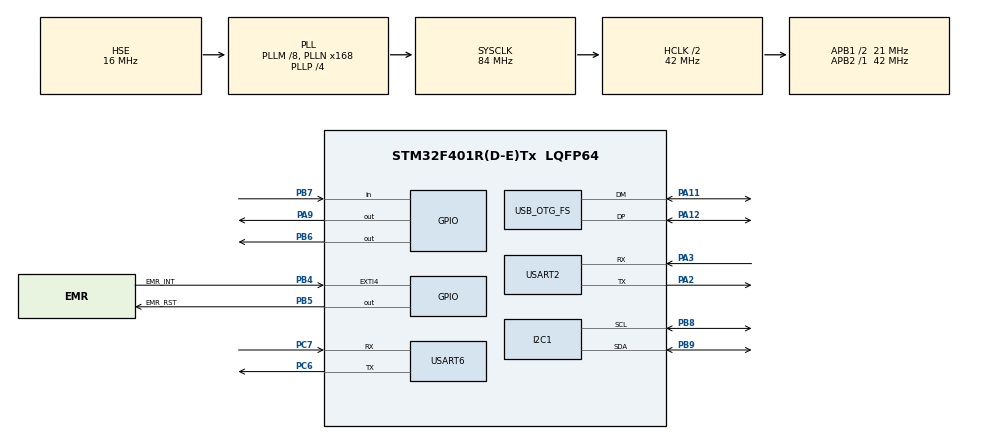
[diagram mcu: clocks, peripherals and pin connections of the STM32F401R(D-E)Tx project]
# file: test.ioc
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I2C1.I2C_Mode=I2C_Fast
Mcu.Family=STM32F4
Mcu.Name=STM32F401R(D-E)Tx
Mcu.Package=LQFP64
NVIC.EXTI4_IRQn=true\:0\:0\:false\:false\:true\:true\:true
NVIC.I2C1_ER_IRQn=true\:0\:0\:false\:false\:true\:true\:true
NVIC.I2C1_EV_IRQn=true\:0\:0\:false\:false\:true\:true\:true
NVIC.OTG_FS_IRQn=true\:0\:0\:false\:false\:true\:false\:true
NVIC.PriorityGroup=NVIC_PRIORITYGROUP_4
NVIC.USART2_IRQn=true\:1\:0\:true\:false\:true\:true\:true
NVIC.USART6_IRQn=true\:3\:0\:true\:false\:true\:true\:true
PA11.Mode=Device_Only
PA11.Signal=USB_OTG_FS_DM
PA12.Mode=Device_Only
PA12.Signal=USB_OTG_FS_DP
PA2.Mode=Asynchronous
PA2.Signal=USART2_TX
PA3.Mode=Asynchronous
PA3.Signal=USART2_RX
PA9.Signal=GPIO_Output
PB4.GPIO_Label=EMR_INT
PB4.GPIO_ModeDefaultEXTI=GPIO_MODE_IT_RISING_FALLING
PB4.Signal=GPXTI4
PB5.GPIO_Label=EMR_RST
PB5.PinState=GPIO_PIN_SET
PB5.Signal=GPIO_Output
PB6.Signal=GPIO_Output
PB7.Signal=GPIO_Input
PB8.Mode=I2C
PB8.Signal=I2C1_SCL
PB9.Mode=I2C
PB9.Signal=I2C1_SDA
PC14-OSC32_IN.Mode=LSE-External-Oscillator
PC14-OSC32_IN.Signal=RCC_OSC32_IN
PC15-OSC32_OUT.Mode=LSE-External-Oscillator
PC15-OSC32_OUT.Signal=RCC_OSC32_OUT
PC6.Mode=Asynchronous
PC6.Signal=USART6_TX
PC7.Mode=Asynchronous
PC7.Signal=USART6_RX
PH0\ -\ OSC_IN.Mode=HSE-External-Oscillator
PH0\ -\ OSC_IN.Signal=RCC_OSC_IN
PH1\ -\ OSC_OUT.Mode=HSE-External-Oscillator
PH1\ -\ OSC_OUT.Signal=RCC_OSC_OUT
ProjectManager.HeapSize=0x400
ProjectManager.StackSize=0x800
ProjectManager.TargetToolchain=MDK-ARM V5.27
RCC.48MHZClocksFreq_Value=48000000
RCC.AHBCLKDivider=RCC_SYSCLK_DIV2
RCC.AHBFreq_Value=42000000
RCC.APB1CLKDivider=RCC_HCLK_DIV2
RCC.APB1Freq_Value=21000000
RCC.APB1TimFreq_Value=42000000
RCC.APB2Freq_Value=42000000
RCC.APB2TimFreq_Value=42000000
RCC.CortexFreq_Value=42000000
RCC.HCLKFreq_Value=42000000
RCC.HSE_VALUE=16000000
RCC.HSI_VALUE=16000000
RCC.PLLM=8
RCC.PLLN=168
RCC.PLLP=RCC_PLLP_DIV4
RCC.PLLQ=7
RCC.SYSCLKFreq_VALUE=84000000
RCC.SYSCLKSource=RCC_SYSCLKSOURCE_PLLCLK
RCC.VCOOutputFreq_Value=336000000
USART2.VirtualMode=VM_ASYNC
USART6.VirtualMode=VM_ASYNC
USB_DEVICE.CLASS_NAME_FS=CUSTOM_HID
USB_DEVICE.VirtualMode-CUSTOM_HID_FS=CustomHid
USB_DEVICE.VirtualModeFS=Custom_Hid_FS
USB_OTG_FS.VirtualMode=Device_Only
VP_USB_DEVICE_VS_USB_DEVICE_CUSTOM_HID_FS.Mode=CUSTOM_HID_FS
board=custom

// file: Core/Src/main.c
/* USER CODE BEGIN Header */
/**
  ******************************************************************************
  * @file           : main.c
  * @brief          : Main program body
  ******************************************************************************
  * @attention
  *
  * <h2><center>&copy; Copyright (c) 2021 STMicroelectronics.
  * All rights reserved.</center></h2>
  *
  * This software component is licensed by ST under Ultimate Liberty license
  * SLA0044, the "License"; You may not use this file except in compliance with
  * the License. You may obtain a copy of the License at:
  *                             www.st.com/SLA0044
  *
  ******************************************************************************
  */
/* USER CODE END Header */
#include "main.h"
#include "usb_device.h"

/* USER CODE BEGIN Includes */
#include "usbd_custom_hid_if.h"
#include <stdio.h>
#include "sw_iic.h"
/* USER CODE END Includes */

/* USER CODE BEGIN PTD */
uint8_t EMR_I2C_ADDR_8BIT = 0x13 ;
#define EMR_I2C_PACKET_SIZE 17
#define REPORT_ID 0x02
uint8_t ROTATION_0_CMD[17] = { 0x11,0xff,0xff,0xff,0xff,0xff,0xff,0xff,0xff,0xff,0xff,0xff,0xff,0xff,0xff,0xff,0x00 };
uint8_t ROTATION_90_CMD[17] = { 0x11,0xff,0xff,0xff,0xff,0xff,0xff,0xff,0xff,0xff,0xff,0xff,0xff,0xff,0xff,0xff,0x01 };
uint8_t EMR_INT = 0 ;
uint8_t OSD_ON = 0 ;
uint8_t OSD_EVENT_RELEASE = 0 ;
extern I2C_HandleTypeDef hi2c1;
extern UART_HandleTypeDef huart6;
extern GPIO_InitTypeDef GPIO_InitStruct ;
uint8_t pData[EMR_I2C_PACKET_SIZE];
uint8_t send_data[128];
uint8_t  aRxBuffer[64];

uint8_t i ;
volatile uint8_t  page_buf[512];

uint8_t  page_buf_full_idx = 0 ,flag_start_fill_page_buf = 0;

uint8_t test_buf[64];

uint32_t press_cnt = 0 ;

/*
	0: pen mode
	1: zoom mode
*/
uint8_t working_mode = 0;

typedef struct
{
	uint8_t KEYPAD_ID ; // 0x01
	/* b0 : left ctrl
		b1 : left shift
		b2 : left alt
		b3 : left GUI
		b4 : right ctrl
		b5 : right shift
		b6 : right alt
		b7 : right GUI
	*/
	uint8_t MODIFIER ;

	uint8_t RESERVED ;
	uint8_t KEYCODE1 ; //0x56 Keypad - ; 0x57 keypad +
	uint8_t KEYCODE2 ;
	uint8_t KEYCODE3 ;
	uint8_t KEYCODE4 ;
	uint8_t KEYCODE5 ;
	uint8_t KEYCODE6 ;
}KeyboardHID ;

KeyboardHID keyboard_hid = {1,0,0,0,0,0,0,0,0};

#define MAX_X   29376
#define MAX_Y	 16524
/* USER CODE END PTD */

/* USER CODE BEGIN PD */
void Handle_EMR_Data();

/* USER CODE END PD */

I2C_HandleTypeDef hi2c1;

UART_HandleTypeDef huart2;
UART_HandleTypeDef huart6;

/* USER CODE BEGIN PV */
extern USBD_HandleTypeDef hUsbDeviceFS;

/* USER CODE END PV */

void SystemClock_Config(void);
static void MX_GPIO_Init(void);
static void MX_I2C1_Init(void);
static void MX_USART2_UART_Init(void);
static void MX_USART6_UART_Init(void);

/* USER CODE BEGIN 0 */
void Delay()
{
	uint16_t d = 0xf;
	while(d--) ;
}
int fputc(int32_t ch, FILE *f)
{
  //  while((USART6->SR&0X40)==0);
   // USART6->DR = (uint8_t) ch;
	HAL_UART_Transmit(&huart6,(uint8_t *)&ch,1,1000);

    return ch;
}

/* Send OSD control data to scaler */
uint8_t Send_OSD_Control_to_Scaler(uint8_t event,uint8_t x_lo,uint8_t x_hi,uint8_t y_lo , uint8_t y_hi)
{
	uint8_t Ack,CheckSum;
	uint8_t data[4] ;
	data[0] = x_lo ;
	data[1] = x_hi ;
	data[2] = y_lo ;
	data[3] = y_hi ;
	//IIC_Start();
	//T_IIC_Tx(0x6e);
	//T_IIC_Tx(event);
	//T_IIC_Tx(x_lo);
	//T_IIC_Tx(x_hi);
	//T_IIC_Tx(y_lo);
	//T_IIC_Tx(y_hi);
	//IIC_Stop();
	HAL_UART_Transmit(&huart2,data,4,1000);
	return Ack;
}

void keypad_zoom_in()
{
	keyboard_hid.KEYPAD_ID = 0x01 ;
	keyboard_hid.MODIFIER = 1 ; //b0=left ctrl
	keyboard_hid.KEYCODE1 = 0x57 ; // keypad +

	USBD_CUSTOM_HID_SendReport_FS((uint8_t*)&keyboard_hid , sizeof(keyboard_hid));
	HAL_Delay(5);
	keyboard_hid.MODIFIER = 0 ; // release
	keyboard_hid.KEYCODE1 = 0 ; // release
	USBD_CUSTOM_HID_SendReport_FS((uint8_t*)&keyboard_hid , sizeof(keyboard_hid));
	HAL_Delay(10);

}

void keypad_zoom_out()
{
	keyboard_hid.KEYPAD_ID = 0x01 ;
	keyboard_hid.MODIFIER = 1 ; //b0=left ctrl
	keyboard_hid.KEYCODE1 = 0x56 ; // keypad -

	USBD_CUSTOM_HID_SendReport_FS((uint8_t*)&keyboard_hid , sizeof(keyboard_hid));
	HAL_Delay(5);
	keyboard_hid.MODIFIER = 0 ; // release
	keyboard_hid.KEYCODE1 = 0 ; // release
	USBD_CUSTOM_HID_SendReport_FS((uint8_t*)&keyboard_hid , sizeof(keyboard_hid));
	HAL_Delay(10);

}

void handle_buffer() {

#if 0
   uint16_t i ;
	printf("usb reveive : \n\r");
  for(i=0 ; i<64 ;i++)
  {
	  printf(",0x%x",aRxBuffer[i]);
  }
	printf("\n\r");
#endif

//	USBD_CUSTOM_HID_SendReport_FS(aRxBuffer,8) ;

	if(flag_start_fill_page_buf)
	{
		if((memcmp(aRxBuffer,CMD_SET_BANK0,11)!= 0)
			&& ( memcmp(aRxBuffer,CMD_SET_BANK1,11)!= 0)
			&& ( memcmp(aRxBuffer,CMD_SET_BANK2,11)!= 0)
			&& ( memcmp(aRxBuffer,CMD_SET_BANK3,11)!= 0)
			&& ( memcmp(aRxBuffer,CMD_START_FLASH,11)!= 0)
			&& ( memcmp(aRxBuffer,CMD_END_FLASH,11)!= 0))
		{

			if(page_buf_full_idx < 16)
			{
				memcpy((page_buf+(32*page_buf_full_idx)),aRxBuffer,32);
				page_buf_full_idx++ ;

			}
		}
		 //USBD_CUSTOM_HID_SendReport_FS(rxBuffer,8) ;
    }
}

void ResetEMR()
{
	HAL_GPIO_WritePin(EMR_RST_GPIO_Port,GPIO_PIN_5,GPIO_PIN_SET);
	HAL_GPIO_WritePin(EMR_RST_GPIO_Port,GPIO_PIN_5,GPIO_PIN_RESET);
	Delay();
	HAL_GPIO_WritePin(EMR_RST_GPIO_Port,GPIO_PIN_5,GPIO_PIN_SET);
//	printf("force to EMR RESET !\n\r");
}

uint8_t EMR_Alive_Check(void)
{
    HAL_StatusTypeDef i2c_res;
    uint8_t	addr_w=0x12;
    //uint8_t	addr_r=0x13;

    i2c_res = HAL_I2C_Master_Transmit( &hi2c1, addr_w, 0x00, 0x01, 10000 );
    if (i2c_res != HAL_OK)
    {

        printf( "EMR Alive Check ERROR. Res = 0x%02X  \r\n",i2c_res );

        ResetEMR();
    }
    else
    {

     //   printf( "EMR Alive Check PASS !!  \r\n");

    }
    return i2c_res;

}

int16_t x ,y ,p;

void Handle_EMR_to_USB()
{

		send_data[0]=REPORT_ID;

		send_data[1]=(pData[3]);

		/*x*/
		x = MAX_X-(pData[4] + (pData[5]<<8)) ;
		if(x<0)return;
		//send_data[2]=(pData[4]);
		//send_data[3]=(pData[5]);
		send_data[2]=(x&0xff);
		send_data[3]=(x>>8);

		/*y*/
		y = MAX_Y-(pData[6] + (pData[7]<<8) ) ;
	   if(y<0)return;
		//send_data[4]=(pData[6]);
		//send_data[5]=(pData[7]);
		send_data[4] = y&0xff ;
		send_data[5]= (y >>8) ;

		/*pressure*/
		send_data[6]=pData[8];//low byte
		send_data[7]=pData[9];//high byte

		 USBD_CUSTOM_HID_SendReport_FS(send_data,8) ;
	//	 send_data[0]=0x03 ;
	//	 USBD_CUSTOM_HID_SendReport_FS(send_data,9) ;

}

uint16_t temp_y ;
uint16_t falling_cnt = 0 ;
uint16_t rising_cnt = 0 ;

#define ZOOM_ONE_SHOT

void Handle_ZOOM_IN_OUT ()
{

	//printf("Tip Switch = %x\n\r",(pData[3]&0x01));
	//uint8_t Tip_Switch = pData[3]&0x01 ;
	y = MAX_Y-(pData[6] + (pData[7]<<8) ) ;
	//printf("Tip Switch = %x\n\r",Tip_Switch);
	//if(Tip_Switch == 1)
	{
		if(y>(temp_y+30))
		{
			falling_cnt ++ ;
			if(falling_cnt == 5)
			{

				keypad_zoom_in();
				falling_cnt =0 ;
				rising_cnt = 0 ;
				temp_y = 0 ;
			}
		}

		else if(y<temp_y-30)
		{
			rising_cnt ++ ;
			if(rising_cnt == 6)
			{

				keypad_zoom_out();
				falling_cnt =0 ;
				rising_cnt = 0 ;
				temp_y = 0 ;
			}
		}
		temp_y = y ;
	}

}

void Handle_EMR_Data ()
{
	uint8_t Barrel_Switch = 0 ;
	uint8_t Tip_Switch = 0 ;
	uint16_t pressure = 0 ;

	if(EMR_INT)
	{
	//	printf("EMR INT\n\r");
		HAL_StatusTypeDef status;

		/*一直讀到中斷Rising Trigger */
		while(1)
		{
			if(EMR_INT == 0) break;
			status =  HAL_I2C_Master_Receive(&hi2c1, EMR_I2C_ADDR_8BIT, pData, EMR_I2C_PACKET_SIZE, 100);

			if(status == HAL_ERROR)
			{
				printf("i2c HAL_ERROR\n\r");
				ResetEMR() ;
				break;

			}
			else if(status == HAL_BUSY)
			{
				printf("i2c HAL_BUSY\n\r");
				ResetEMR() ;
				break;
			}
			else if(status == HAL_TIMEOUT)
			{
				printf("i2c HAL_TIMEOUT\n\r");
				ResetEMR() ;
				break;
			}
			else if (status == HAL_OK)
			{
#if 0
			printf("receive EMR Data %d\n\r",EMR_I2C_PACKET_SIZE);
			for(i=0;i<EMR_I2C_PACKET_SIZE ; i++ )
				printf("%x, ",pData[i]);
			printf("\n\r");
//			printf("Tx=%d , Ty=%d \n\r",(pData[11]+pData[12]<<8),(pData[13]+pData[14]<<8));
#endif
	//	 USBD_CUSTOM_HID_SendReport_FS(pData,EMR_I2C_PACKET_SIZE) ;

			//send_data[6]=pData[8];//low byte
		   //send_data[7]=pData[9];//high byte

#if 0
				printf("Tip Switch = %x\n\r",(pData[3]&0x01));
				printf("Barrel Switch = %x\n\r",(pData[3]&0x02)>>1);
				printf("Eraser = %x\n\r",(pData[3]&0x04)>>2);
				printf("Invert = %x\n\r",(pData[3]&0x08)>>3);
				printf("In Range = %x\n\r",(pData[3]&0x20)>>5);
				printf("Pressure = %x\n\r",(pData[8] + (pData[9] <<8)));
				printf("*************************************\n\r");
#endif
			/*test function" OSD_ON always 1*/
			OSD_ON = 1 ;
			/*check OSD detect pin , normal mode*/
			if(OSD_ON == 0)
			{

				Barrel_Switch = (pData[3]&0x02)>>1 ;
				Tip_Switch = pData[3]&0x01 ;
				if(Barrel_Switch == 1 && Tip_Switch == 1)
				{
					press_cnt ++ ;
					if(press_cnt % 29 ==0)
					{

						Handle_ZOOM_IN_OUT ();
					}
				}

				else if(Barrel_Switch == 1 && Tip_Switch == 0)
				{
					falling_cnt =0 ;
					rising_cnt = 0 ;
					temp_y = 0 ;

					press_cnt = 0 ;
				}
				else
				{
					falling_cnt =0 ;
					rising_cnt = 0 ;
					temp_y = 0 ;

					press_cnt = 0 ;
					Handle_EMR_to_USB();
				}

			}
			else if(OSD_ON == 1)
			{
				/*check OSD detect pin , OSD mode*/
				pressure = pData[8] + (pData[9] <<8) ;
				if(pressure == 0)
				{
					OSD_EVENT_RELEASE = 1;

				}

				if(OSD_EVENT_RELEASE == 1)
				{
					if(pressure > 1000 )
					{
						OSD_EVENT_RELEASE = 0;
						/* Send data to scaler to control menu  */
						Send_OSD_Control_to_Scaler(0x61,0x62,0x63,0x64,0x65);
					//	printf("click!");

					}
				}

			}

		}
	}
		EMR_Alive_Check();

}

}

/* EMR Interrupt */
void HAL_GPIO_EXTI_Callback(uint16_t GPIO_Pin)
{
	if(GPIO_Pin == EMR_INT_Pin)
	{
		if(HAL_GPIO_ReadPin(EMR_INT_GPIO_Port,EMR_INT_Pin) == RESET)
		{
			EMR_INT = 1;
		//	printf("1");
		}
		else
		{
			EMR_INT = 0;
		//	printf("0");
		}

	//	Handle_EMR_Data ();
	}
	if(GPIO_Pin == GPIO_PIN_2)
	{
	//	printf("2\n\r");
	}
#if 0
	if(GPIO_Pin == OSD_MENU_DETECT_Pin)
	{
		if(HAL_GPIO_ReadPin(GPIOC,OSD_MENU_DETECT_Pin) == RESET)
		{
			OSD_ON = 1;
			printf("OSD_ON\n\r");
		}
		else
		{
		  OSD_ON = 0;
			printf("OSD_OFF\n\r");
		}
	}
#endif
}

/* USER CODE END 0 */

int main(void)
{
  /* USER CODE BEGIN 1 */
	uint8_t send_data[64];
	uint8_t i =0 ;

  /* USER CODE END 1 */

  /* MCU Configuration--------------------------------------------------------*/

  /* Reset of all peripherals, Initializes the Flash interface and the Systick. */
  HAL_Init();

  /* Configure the system clock */
  SystemClock_Config();

  /* Initialize all configured peripherals */
  MX_GPIO_Init();
  MX_USB_DEVICE_Init();
  MX_I2C1_Init();
  MX_USART2_UART_Init();
  MX_USART6_UART_Init();
  /* USER CODE BEGIN 2 */
	printf("boot done\n\r");

	 // HAL_Delay(5000);
  /* USER CODE END 2 */

  /* Infinite loop */
  while (1)
  {

    /* USER CODE BEGIN 3 */

	  if( memcmp(aRxBuffer,CMD_START_FLASH,11)== 0)
	  {
			printf("enter isp\n\r");

		   ISP_Process();
	  }
	  HAL_Delay(2000);
	  Send_OSD_Control_to_Scaler(0x61,0x62,0x63,0x64,0x65);

#if 0
	  HAL_Delay(1000);
	 test_process();

#endif
     Handle_EMR_Data () ;

  //USBD_CUSTOM_HID_SendReport(&hUsbDeviceFS,send_data,9);
  }
  /* USER CODE END 3 */
}

void SystemClock_Config(void)
{
  RCC_OscInitTypeDef RCC_OscInitStruct = {0};
  RCC_ClkInitTypeDef RCC_ClkInitStruct = {0};

  /** Configure the main internal regulator output voltage
  */
  __HAL_RCC_PWR_CLK_ENABLE();
  __HAL_PWR_VOLTAGESCALING_CONFIG(PWR_REGULATOR_VOLTAGE_SCALE2);
  /** Initializes the RCC Oscillators according to the specified parameters
  * in the RCC_OscInitTypeDef structure.
  */
  RCC_OscInitStruct.OscillatorType = RCC_OSCILLATORTYPE_HSE;
  RCC_OscInitStruct.HSEState = RCC_HSE_ON;
  RCC_OscInitStruct.PLL.PLLState = RCC_PLL_ON;
  RCC_OscInitStruct.PLL.PLLSource = RCC_PLLSOURCE_HSE;
  RCC_OscInitStruct.PLL.PLLM = 8;
  RCC_OscInitStruct.PLL.PLLN = 168;
  RCC_OscInitStruct.PLL.PLLP = RCC_PLLP_DIV4;
  RCC_OscInitStruct.PLL.PLLQ = 7;
  if (HAL_RCC_OscConfig(&RCC_OscInitStruct) != HAL_OK)
  {
    Error_Handler();
  }
  /** Initializes the CPU, AHB and APB buses clocks
  */
  RCC_ClkInitStruct.ClockType = RCC_CLOCKTYPE_HCLK|RCC_CLOCKTYPE_SYSCLK
                              |RCC_CLOCKTYPE_PCLK1|RCC_CLOCKTYPE_PCLK2;
  RCC_ClkInitStruct.SYSCLKSource = RCC_SYSCLKSOURCE_PLLCLK;
  RCC_ClkInitStruct.AHBCLKDivider = RCC_SYSCLK_DIV2;
  RCC_ClkInitStruct.APB1CLKDivider = RCC_HCLK_DIV2;
  RCC_ClkInitStruct.APB2CLKDivider = RCC_HCLK_DIV1;

  if (HAL_RCC_ClockConfig(&RCC_ClkInitStruct, FLASH_LATENCY_1) != HAL_OK)
  {
    Error_Handler();
  }
}

static void MX_I2C1_Init(void)
{

  hi2c1.Instance = I2C1;
  hi2c1.Init.ClockSpeed = 400000;
  hi2c1.Init.DutyCycle = I2C_DUTYCYCLE_2;
  hi2c1.Init.OwnAddress1 = 0;
  hi2c1.Init.AddressingMode = I2C_ADDRESSINGMODE_7BIT;
  hi2c1.Init.DualAddressMode = I2C_DUALADDRESS_DISABLE;
  hi2c1.Init.OwnAddress2 = 0;
  hi2c1.Init.GeneralCallMode = I2C_GENERALCALL_DISABLE;
  hi2c1.Init.NoStretchMode = I2C_NOSTRETCH_DISABLE;
  if (HAL_I2C_Init(&hi2c1) != HAL_OK)
  {
    Error_Handler();
  }

}

static void MX_USART2_UART_Init(void)
{

  huart2.Instance = USART2;
  huart2.Init.BaudRate = 115200;
  huart2.Init.WordLength = UART_WORDLENGTH_8B;
  huart2.Init.StopBits = UART_STOPBITS_1;
  huart2.Init.Parity = UART_PARITY_NONE;
  huart2.Init.Mode = UART_MODE_TX_RX;
  huart2.Init.HwFlowCtl = UART_HWCONTROL_NONE;
  huart2.Init.OverSampling = UART_OVERSAMPLING_16;
  if (HAL_UART_Init(&huart2) != HAL_OK)
  {
    Error_Handler();
  }

}

static void MX_USART6_UART_Init(void)
{

  huart6.Instance = USART6;
  huart6.Init.BaudRate = 115200;
  huart6.Init.WordLength = UART_WORDLENGTH_8B;
  huart6.Init.StopBits = UART_STOPBITS_1;
  huart6.Init.Parity = UART_PARITY_NONE;
  huart6.Init.Mode = UART_MODE_TX_RX;
  huart6.Init.HwFlowCtl = UART_HWCONTROL_NONE;
  huart6.Init.OverSampling = UART_OVERSAMPLING_16;
  if (HAL_UART_Init(&huart6) != HAL_OK)
  {
    Error_Handler();
  }

}

static void MX_GPIO_Init(void)
{
  GPIO_InitTypeDef GPIO_InitStruct = {0};

  /* GPIO Ports Clock Enable */
  __HAL_RCC_GPIOC_CLK_ENABLE();
  __HAL_RCC_GPIOH_CLK_ENABLE();
  __HAL_RCC_GPIOA_CLK_ENABLE();
  __HAL_RCC_GPIOB_CLK_ENABLE();

    /*Configure GPIO pin Output Level */
  HAL_GPIO_WritePin(SW_IIC_SDA_GPIO_Port, SW_IIC_SDA_Pin, GPIO_PIN_SET);

  /*Configure GPIO pin Output Level */
  HAL_GPIO_WritePin(SW_IIC_SCL_GPIO_Port, SW_IIC_SCL_Pin, GPIO_PIN_SET);

  /*Configure GPIO pin Output Level */
  HAL_GPIO_WritePin(GPIOA, GPIO_PIN_9, GPIO_PIN_RESET);

  /*Configure GPIO pin Output Level */
  HAL_GPIO_WritePin(EMR_RST_GPIO_Port, EMR_RST_Pin, GPIO_PIN_SET);

  /*Configure GPIO pin Output Level */
  HAL_GPIO_WritePin(GPIOB, GPIO_PIN_6, GPIO_PIN_RESET);

   /*Configure GPIO pin : PtPin */
  GPIO_InitStruct.Pin = SW_IIC_SDA_Pin;
  GPIO_InitStruct.Mode = GPIO_MODE_OUTPUT_PP;
  GPIO_InitStruct.Pull = GPIO_PULLUP;
  GPIO_InitStruct.Speed = GPIO_SPEED_FAST;
  HAL_GPIO_Init(SW_IIC_SDA_GPIO_Port, &GPIO_InitStruct);

  /*Configure GPIO pin : PtPin */
  GPIO_InitStruct.Pin = SW_IIC_SCL_Pin;
  GPIO_InitStruct.Mode = GPIO_MODE_OUTPUT_PP;
  GPIO_InitStruct.Pull = GPIO_PULLUP;
  GPIO_InitStruct.Speed = GPIO_SPEED_FAST;
  HAL_GPIO_Init(SW_IIC_SCL_GPIO_Port, &GPIO_InitStruct);

  /*Configure GPIO pin : PA9 */
  GPIO_InitStruct.Pin = GPIO_PIN_9;
  GPIO_InitStruct.Mode = GPIO_MODE_OUTPUT_PP;
  GPIO_InitStruct.Pull = GPIO_NOPULL;
  GPIO_InitStruct.Speed = GPIO_SPEED_FREQ_LOW;
  HAL_GPIO_Init(GPIOA, &GPIO_InitStruct);

  /*Configure GPIO pin : EMR_INT_Pin */
  GPIO_InitStruct.Pin = EMR_INT_Pin;
  GPIO_InitStruct.Mode = GPIO_MODE_IT_RISING_FALLING;
  GPIO_InitStruct.Pull = GPIO_NOPULL;
  HAL_GPIO_Init(EMR_INT_GPIO_Port, &GPIO_InitStruct);

  /*Configure GPIO pins : EMR_RST_Pin PB6 */
  GPIO_InitStruct.Pin = EMR_RST_Pin|GPIO_PIN_6;
  GPIO_InitStruct.Mode = GPIO_MODE_OUTPUT_PP;
  GPIO_InitStruct.Pull = GPIO_NOPULL;
  GPIO_InitStruct.Speed = GPIO_SPEED_FREQ_LOW;
  HAL_GPIO_Init(GPIOB, &GPIO_InitStruct);

  /*Configure GPIO pin : PB7 */
  GPIO_InitStruct.Pin = GPIO_PIN_7;
  GPIO_InitStruct.Mode = GPIO_MODE_INPUT;
  GPIO_InitStruct.Pull = GPIO_NOPULL;
  HAL_GPIO_Init(GPIOB, &GPIO_InitStruct);

  /*Configure GPIO pin : PC12*/
  GPIO_InitStruct.Pin = OSD_MENU_DETECT_Pin;
  GPIO_InitStruct.Mode = GPIO_MODE_IT_RISING_FALLING;
  GPIO_InitStruct.Pull = GPIO_NOPULL;
  HAL_GPIO_Init(GPIOC, &GPIO_InitStruct);

  /* EXTI interrupt init*/
  HAL_NVIC_SetPriority(EXTI4_IRQn, 0, 0);
  HAL_NVIC_EnableIRQ(EXTI4_IRQn);

}

void Error_Handler(void)
{
  __disable_irq();
  while (1)
  {
  }
}

/************************ (C) COPYRIGHT STMicroelectronics *****END OF FILE****/
